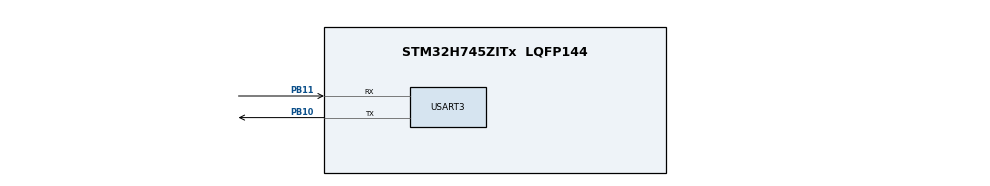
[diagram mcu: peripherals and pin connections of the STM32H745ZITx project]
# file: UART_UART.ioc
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CORTEX_M7.default_mode_Activation=1
CortexM4.IPs=BDMA,CORTEX_M4\:I,DMA,FATFS_M4\:I,FREERTOS_M4\:I,GPIO,IWDG2\:I,MDMA,NVIC2\:I,OPENAMP_M4\:I,PDM2PCM_M4\:I,PWR,RCC,RESMGR_UTILITY,SYS_M4\:I,USB_DEVICE_M4\:I,USB_HOST_M4\:I,VREFBUF,WWDG2\:I
CortexM7.IPs=BDMA\:I,CORTEX_M7\:I,DMA\:I,FATFS_M7\:I,FREERTOS_M7\:I,GPIO\:I,IWDG1\:I,MDMA\:I,NVIC1\:I,OPENAMP_M7\:I,PDM2PCM_M7\:I,PWR\:I,RCC\:I,RESMGR_UTILITY\:I,SYS\:I,USB_DEVICE_M7\:I,USB_HOST_M7\:I,VREFBUF\:I,WWDG1\:I,MEMORYMAP\:I,USART3\:I
Mcu.Family=STM32H7
Mcu.Name=STM32H745ZITx
Mcu.Package=LQFP144
NVIC1.PriorityGroup=NVIC_PRIORITYGROUP_4
NVIC1.USART3_IRQn=true\:0\:0\:false\:false\:true\:true\:true\:true
NVIC2.PriorityGroup=NVIC_PRIORITYGROUP_4
PB10.Mode=Asynchronous
PB10.PinAttribute=CortexM7
PB10.Signal=USART3_TX
PB11.Mode=Asynchronous
PB11.PinAttribute=CortexM7
PB11.Signal=USART3_RX
ProjectManager.HeapSize=M4-0x200,M7-0x200
ProjectManager.StackSize=M4-0x400,M7-0x400
ProjectManager.TargetToolchain=STM32CubeIDE
RCC.ADCFreq_Value=129000000
RCC.APB1Freq_Value=32000000
RCC.APB2Freq_Value=64000000
RCC.APB3Freq_Value=64000000
RCC.APB4Freq_Value=64000000
RCC.CortexFreq_Value=64000000
RCC.D2PPRE1=RCC_APB1_DIV2
RCC.HCLKFreq_Value=64000000
RCC.SYSCLKFreq_VALUE=64000000
RCC.USBFreq_Value=129000000
SYS.userName=SYS_M7
USART3.VirtualMode-Asynchronous=VM_ASYNC
VP_MEMORYMAP_VS_MEMORYMAP.Mode=CurAppReg
VP_SYS_M4_VS_Systick.Mode=SysTick
board=custom

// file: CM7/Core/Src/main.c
/* USER CODE BEGIN Header */
/**
  ******************************************************************************
  * @file           : main.c
  * @brief          : UART Echo simple para STM32H745 Nucleo-144
  ******************************************************************************
  */
/* USER CODE END Header */

#include "main.h"
#include <string.h>

UART_HandleTypeDef huart3;

void SystemClock_Config(void);
static void MX_GPIO_Init(void);
static void MX_USART3_UART_Init(void);

int main(void)
{
  /* MCU Configuration--------------------------------------------------------*/
  HAL_Init();
  SystemClock_Config();
  MX_GPIO_Init();
  MX_USART3_UART_Init();

  uint8_t rxData;
  char msg[] = "UART Echo Ready - STM32H745\r\n";

  // Enviar mensaje de inicio
  HAL_UART_Transmit(&huart3, (uint8_t*)msg, strlen(msg), HAL_MAX_DELAY);

  /* Infinite loop */
  while (1)
  {
    // Recibir un byte
    if (HAL_UART_Receive(&huart3, &rxData, 1, 100) == HAL_OK)
    {
      // Hacer echo del byte recibido
      HAL_UART_Transmit(&huart3, &rxData, 1, HAL_MAX_DELAY);

      // Encender LED verde al recibir datos
      HAL_GPIO_TogglePin(GPIOB, GPIO_PIN_0);
    }
  }
}

static void MX_USART3_UART_Init(void)
{
  huart3.Instance = USART3;
  huart3.Init.BaudRate = 115200;
  huart3.Init.WordLength = UART_WORDLENGTH_8B;
  huart3.Init.StopBits = UART_STOPBITS_1;
  huart3.Init.Parity = UART_PARITY_NONE;
  huart3.Init.Mode = UART_MODE_TX_RX;
  huart3.Init.HwFlowCtl = UART_HWCONTROL_NONE;
  huart3.Init.OverSampling = UART_OVERSAMPLING_16;
  huart3.Init.OneBitSampling = UART_ONE_BIT_SAMPLE_DISABLE;
  huart3.Init.ClockPrescaler = UART_PRESCALER_DIV1;
  huart3.AdvancedInit.AdvFeatureInit = UART_ADVFEATURE_NO_INIT;

  if (HAL_UART_Init(&huart3) != HAL_OK)
  {
    Error_Handler();
  }
}

static void MX_GPIO_Init(void)
{
  GPIO_InitTypeDef GPIO_InitStruct = {0};

  /* GPIO Ports Clock Enable */
  __HAL_RCC_GPIOB_CLK_ENABLE();
  __HAL_RCC_GPIOD_CLK_ENABLE();

  /* Configure GPIO pin Output Level */
  HAL_GPIO_WritePin(GPIOB, GPIO_PIN_0, GPIO_PIN_RESET);

  /* Configure GPIO pin : PB0 (LED Verde) */
  GPIO_InitStruct.Pin = GPIO_PIN_0;
  GPIO_InitStruct.Mode = GPIO_MODE_OUTPUT_PP;
  GPIO_InitStruct.Pull = GPIO_NOPULL;
  GPIO_InitStruct.Speed = GPIO_SPEED_FREQ_LOW;
  HAL_GPIO_Init(GPIOB, &GPIO_InitStruct);
}

void SystemClock_Config(void)
{
  RCC_OscInitTypeDef RCC_OscInitStruct = {0};
  RCC_ClkInitTypeDef RCC_ClkInitStruct = {0};

  /** Supply configuration update enable */
  HAL_PWREx_ConfigSupply(PWR_LDO_SUPPLY);

  /** Configure the main internal regulator output voltage */
  __HAL_PWR_VOLTAGESCALING_CONFIG(PWR_REGULATOR_VOLTAGE_SCALE1);

  while(!__HAL_PWR_GET_FLAG(PWR_FLAG_VOSRDY)) {}

  /** Initializes the RCC Oscillators */
  RCC_OscInitStruct.OscillatorType = RCC_OSCILLATORTYPE_HSI;
  RCC_OscInitStruct.HSIState = RCC_HSI_DIV1;
  RCC_OscInitStruct.HSICalibrationValue = RCC_HSICALIBRATION_DEFAULT;
  RCC_OscInitStruct.PLL.PLLState = RCC_PLL_ON;
  RCC_OscInitStruct.PLL.PLLSource = RCC_PLLSOURCE_HSI;
  RCC_OscInitStruct.PLL.PLLM = 4;
  RCC_OscInitStruct.PLL.PLLN = 50;
  RCC_OscInitStruct.PLL.PLLP = 2;
  RCC_OscInitStruct.PLL.PLLQ = 2;
  RCC_OscInitStruct.PLL.PLLR = 2;
  RCC_OscInitStruct.PLL.PLLRGE = RCC_PLL1VCIRANGE_3;
  RCC_OscInitStruct.PLL.PLLVCOSEL = RCC_PLL1VCOWIDE;
  RCC_OscInitStruct.PLL.PLLFRACN = 0;

  if (HAL_RCC_OscConfig(&RCC_OscInitStruct) != HAL_OK)
  {
    Error_Handler();
  }

  /** Initializes the CPU, AHB and APB buses clocks */
  RCC_ClkInitStruct.ClockType = RCC_CLOCKTYPE_HCLK|RCC_CLOCKTYPE_SYSCLK
                              |RCC_CLOCKTYPE_PCLK1|RCC_CLOCKTYPE_PCLK2
                              |RCC_CLOCKTYPE_D3PCLK1|RCC_CLOCKTYPE_D1PCLK1;
  RCC_ClkInitStruct.SYSCLKSource = RCC_SYSCLKSOURCE_PLLCLK;
  RCC_ClkInitStruct.SYSCLKDivider = RCC_SYSCLK_DIV1;
  RCC_ClkInitStruct.AHBCLKDivider = RCC_HCLK_DIV2;
  RCC_ClkInitStruct.APB3CLKDivider = RCC_APB3_DIV2;
  RCC_ClkInitStruct.APB1CLKDivider = RCC_APB1_DIV2;
  RCC_ClkInitStruct.APB2CLKDivider = RCC_APB2_DIV2;
  RCC_ClkInitStruct.APB4CLKDivider = RCC_APB4_DIV2;

  if (HAL_RCC_ClockConfig(&RCC_ClkInitStruct, FLASH_LATENCY_2) != HAL_OK)
  {
    Error_Handler();
  }
}

void Error_Handler(void)
{
  __disable_irq();
  while (1)
  {
  }
}
